VERSION 5.7 ;
BUSBITCHARS "[]" ;
DIVIDERCHAR "/" ;

UNITS
  DATABASE MICRONS 2000 ;
END UNITS

SITE core7
  CLASS CORE ;
  SIZE 0.38 BY 2.8 ;
END core7

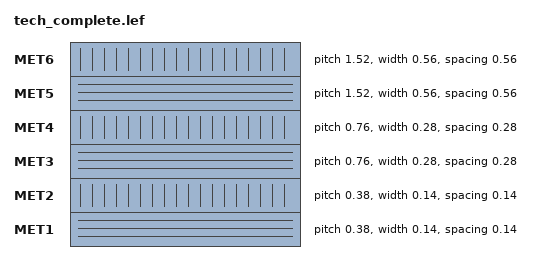
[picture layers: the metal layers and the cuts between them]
LAYER MET1
  TYPE ROUTING ;
  WIDTH 0.14 ;
  SPACING 0.14 ;
  PITCH 0.38 ;
  DIRECTION HORIZONTAL ;
  RESISTANCE RPERSQ 0.08 ;
  CAPACITANCE CPERSQDIST 0.00016 ;
END MET1

LAYER MET2
  TYPE ROUTING ;
  WIDTH 0.14 ;
  SPACING 0.14 ;
  PITCH 0.38 ;
  DIRECTION VERTICAL ;
  RESISTANCE RPERSQ 0.08 ;
  CAPACITANCE CPERSQDIST 0.00016 ;
END MET2

LAYER MET3
  TYPE ROUTING ;
  WIDTH 0.28 ;
  SPACING 0.28 ;
  PITCH 0.76 ;
  DIRECTION HORIZONTAL ;
  RESISTANCE RPERSQ 0.04 ;
  CAPACITANCE CPERSQDIST 0.00014 ;
END MET3

LAYER MET4
  TYPE ROUTING ;
  WIDTH 0.28 ;
  SPACING 0.28 ;
  PITCH 0.76 ;
  DIRECTION VERTICAL ;
  RESISTANCE RPERSQ 0.04 ;
  CAPACITANCE CPERSQDIST 0.00014 ;
END MET4

LAYER MET5
  TYPE ROUTING ;
  WIDTH 0.56 ;
  SPACING 0.56 ;
  PITCH 1.52 ;
  DIRECTION HORIZONTAL ;
  RESISTANCE RPERSQ 0.02 ;
  CAPACITANCE CPERSQDIST 0.00012 ;
END MET5

LAYER MET6
  TYPE ROUTING ;
  WIDTH 0.56 ;
  SPACING 0.56 ;
  PITCH 1.52 ;
  DIRECTION VERTICAL ;
  RESISTANCE RPERSQ 0.02 ;
  CAPACITANCE CPERSQDIST 0.00012 ;
END MET6

END LIBRARY
